# Generated deterministically by seda-macro-lef-normalizer-v1; recipe orfs-asap7-fakeram-m4-v1.
VERSION 5.8 ;
BUSBITCHARS "[]" ;
DIVIDERCHAR "/" ;

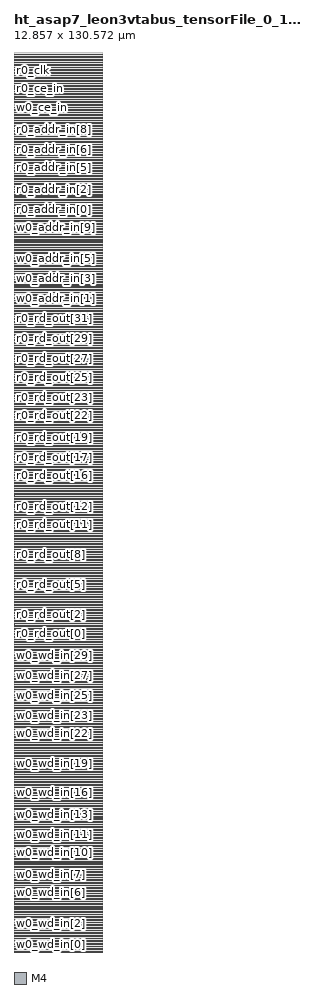
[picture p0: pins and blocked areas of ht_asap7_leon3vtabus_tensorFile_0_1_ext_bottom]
MACRO ht_asap7_leon3vtabus_tensorFile_0_1_ext_bottom
  FOREIGN ht_asap7_leon3vtabus_tensorFile_0_1_ext_bottom 0 0 ;
  CLASS BLOCK ;
  ORIGIN 0 0 ;
  SIZE 12.857 BY 130.572 ;
  SYMMETRY X Y R90 ;
  PIN w0_wd_in[0]
    DIRECTION INPUT ;
    USE SIGNAL ;
    SHAPE ABUTMENT ;
    PORT
      LAYER M4 ;
      RECT 0 0.048 0.024 0.072 ;
    END
  END w0_wd_in[0]
  PIN w0_wd_in[1]
    DIRECTION INPUT ;
    USE SIGNAL ;
    SHAPE ABUTMENT ;
    PORT
      LAYER M4 ;
      RECT 0 1.488 0.024 1.512 ;
    END
  END w0_wd_in[1]
  PIN w0_wd_in[2]
    DIRECTION INPUT ;
    USE SIGNAL ;
    SHAPE ABUTMENT ;
    PORT
      LAYER M4 ;
      RECT 0 2.928 0.024 2.952 ;
    END
  END w0_wd_in[2]
  PIN w0_wd_in[3]
    DIRECTION INPUT ;
    USE SIGNAL ;
    SHAPE ABUTMENT ;
    PORT
      LAYER M4 ;
      RECT 0 4.368 0.024 4.392 ;
    END
  END w0_wd_in[3]
  PIN w0_wd_in[4]
    DIRECTION INPUT ;
    USE SIGNAL ;
    SHAPE ABUTMENT ;
    PORT
      LAYER M4 ;
      RECT 0 5.808 0.024 5.832 ;
    END
  END w0_wd_in[4]
  PIN w0_wd_in[5]
    DIRECTION INPUT ;
    USE SIGNAL ;
    SHAPE ABUTMENT ;
    PORT
      LAYER M4 ;
      RECT 0 7.248 0.024 7.272 ;
    END
  END w0_wd_in[5]
  PIN w0_wd_in[6]
    DIRECTION INPUT ;
    USE SIGNAL ;
    SHAPE ABUTMENT ;
    PORT
      LAYER M4 ;
      RECT 0 8.688 0.024 8.712 ;
    END
  END w0_wd_in[6]
  PIN w0_wd_in[7]
    DIRECTION INPUT ;
    USE SIGNAL ;
    SHAPE ABUTMENT ;
    PORT
      LAYER M4 ;
      RECT 0 10.128 0.024 10.152 ;
    END
  END w0_wd_in[7]
  PIN w0_wd_in[8]
    DIRECTION INPUT ;
    USE SIGNAL ;
    SHAPE ABUTMENT ;
    PORT
      LAYER M4 ;
      RECT 0 11.568 0.024 11.592 ;
    END
  END w0_wd_in[8]
  PIN w0_wd_in[9]
    DIRECTION INPUT ;
    USE SIGNAL ;
    SHAPE ABUTMENT ;
    PORT
      LAYER M4 ;
      RECT 0 13.008 0.024 13.032 ;
    END
  END w0_wd_in[9]
  PIN w0_wd_in[10]
    DIRECTION INPUT ;
    USE SIGNAL ;
    SHAPE ABUTMENT ;
    PORT
      LAYER M4 ;
      RECT 0 14.448 0.024 14.472 ;
    END
  END w0_wd_in[10]
  PIN w0_wd_in[11]
    DIRECTION INPUT ;
    USE SIGNAL ;
    SHAPE ABUTMENT ;
    PORT
      LAYER M4 ;
      RECT 0 15.888 0.024 15.912 ;
    END
  END w0_wd_in[11]
  PIN w0_wd_in[12]
    DIRECTION INPUT ;
    USE SIGNAL ;
    SHAPE ABUTMENT ;
    PORT
      LAYER M4 ;
      RECT 0 17.328 0.024 17.352 ;
    END
  END w0_wd_in[12]
  PIN w0_wd_in[13]
    DIRECTION INPUT ;
    USE SIGNAL ;
    SHAPE ABUTMENT ;
    PORT
      LAYER M4 ;
      RECT 0 18.768 0.024 18.792 ;
    END
  END w0_wd_in[13]
  PIN w0_wd_in[14]
    DIRECTION INPUT ;
    USE SIGNAL ;
    SHAPE ABUTMENT ;
    PORT
      LAYER M4 ;
      RECT 0 20.208 0.024 20.232 ;
    END
  END w0_wd_in[14]
  PIN w0_wd_in[15]
    DIRECTION INPUT ;
    USE SIGNAL ;
    SHAPE ABUTMENT ;
    PORT
      LAYER M4 ;
      RECT 0 21.648 0.024 21.672 ;
    END
  END w0_wd_in[15]
  PIN w0_wd_in[16]
    DIRECTION INPUT ;
    USE SIGNAL ;
    SHAPE ABUTMENT ;
    PORT
      LAYER M4 ;
      RECT 0 23.088 0.024 23.112 ;
    END
  END w0_wd_in[16]
  PIN w0_wd_in[17]
    DIRECTION INPUT ;
    USE SIGNAL ;
    SHAPE ABUTMENT ;
    PORT
      LAYER M4 ;
      RECT 0 24.528 0.024 24.552 ;
    END
  END w0_wd_in[17]
  PIN w0_wd_in[18]
    DIRECTION INPUT ;
    USE SIGNAL ;
    SHAPE ABUTMENT ;
    PORT
      LAYER M4 ;
      RECT 0 25.968 0.024 25.992 ;
    END
  END w0_wd_in[18]
  PIN w0_wd_in[19]
    DIRECTION INPUT ;
    USE SIGNAL ;
    SHAPE ABUTMENT ;
    PORT
      LAYER M4 ;
      RECT 0 27.408 0.024 27.432 ;
    END
  END w0_wd_in[19]
  PIN w0_wd_in[20]
    DIRECTION INPUT ;
    USE SIGNAL ;
    SHAPE ABUTMENT ;
    PORT
      LAYER M4 ;
      RECT 0 28.848 0.024 28.872 ;
    END
  END w0_wd_in[20]
  PIN w0_wd_in[21]
    DIRECTION INPUT ;
    USE SIGNAL ;
    SHAPE ABUTMENT ;
    PORT
      LAYER M4 ;
      RECT 0 30.288 0.024 30.312 ;
    END
  END w0_wd_in[21]
  PIN w0_wd_in[22]
    DIRECTION INPUT ;
    USE SIGNAL ;
    SHAPE ABUTMENT ;
    PORT
      LAYER M4 ;
      RECT 0 31.728 0.024 31.752 ;
    END
  END w0_wd_in[22]
  PIN w0_wd_in[23]
    DIRECTION INPUT ;
    USE SIGNAL ;
    SHAPE ABUTMENT ;
    PORT
      LAYER M4 ;
      RECT 0 33.168 0.024 33.192 ;
    END
  END w0_wd_in[23]
  PIN w0_wd_in[24]
    DIRECTION INPUT ;
    USE SIGNAL ;
    SHAPE ABUTMENT ;
    PORT
      LAYER M4 ;
      RECT 0 34.608 0.024 34.632 ;
    END
  END w0_wd_in[24]
  PIN w0_wd_in[25]
    DIRECTION INPUT ;
    USE SIGNAL ;
    SHAPE ABUTMENT ;
    PORT
      LAYER M4 ;
      RECT 0 36.048 0.024 36.072 ;
    END
  END w0_wd_in[25]
  PIN w0_wd_in[26]
    DIRECTION INPUT ;
    USE SIGNAL ;
    SHAPE ABUTMENT ;
    PORT
      LAYER M4 ;
      RECT 0 37.488 0.024 37.512 ;
    END
  END w0_wd_in[26]
  PIN w0_wd_in[27]
    DIRECTION INPUT ;
    USE SIGNAL ;
    SHAPE ABUTMENT ;
    PORT
      LAYER M4 ;
      RECT 0 38.928 0.024 38.952 ;
    END
  END w0_wd_in[27]
  PIN w0_wd_in[28]
    DIRECTION INPUT ;
    USE SIGNAL ;
    SHAPE ABUTMENT ;
    PORT
      LAYER M4 ;
      RECT 0 40.368 0.024 40.392 ;
    END
  END w0_wd_in[28]
  PIN w0_wd_in[29]
    DIRECTION INPUT ;
    USE SIGNAL ;
    SHAPE ABUTMENT ;
    PORT
      LAYER M4 ;
      RECT 0 41.808 0.024 41.832 ;
    END
  END w0_wd_in[29]
  PIN w0_wd_in[30]
    DIRECTION INPUT ;
    USE SIGNAL ;
    SHAPE ABUTMENT ;
    PORT
      LAYER M4 ;
      RECT 0 43.248 0.024 43.272 ;
    END
  END w0_wd_in[30]
  PIN w0_wd_in[31]
    DIRECTION INPUT ;
    USE SIGNAL ;
    SHAPE ABUTMENT ;
    PORT
      LAYER M4 ;
      RECT 0 44.688 0.024 44.712 ;
    END
  END w0_wd_in[31]
  PIN r0_rd_out[0]
    DIRECTION OUTPUT ;
    USE SIGNAL ;
    SHAPE ABUTMENT ;
    PORT
      LAYER M4 ;
      RECT 0 46.128 0.024 46.152 ;
    END
  END r0_rd_out[0]
  PIN r0_rd_out[1]
    DIRECTION OUTPUT ;
    USE SIGNAL ;
    SHAPE ABUTMENT ;
    PORT
      LAYER M4 ;
      RECT 0 47.568 0.024 47.592 ;
    END
  END r0_rd_out[1]
  PIN r0_rd_out[2]
    DIRECTION OUTPUT ;
    USE SIGNAL ;
    SHAPE ABUTMENT ;
    PORT
      LAYER M4 ;
      RECT 0 49.008 0.024 49.032 ;
    END
  END r0_rd_out[2]
  PIN r0_rd_out[3]
    DIRECTION OUTPUT ;
    USE SIGNAL ;
    SHAPE ABUTMENT ;
    PORT
      LAYER M4 ;
      RECT 0 50.448 0.024 50.472 ;
    END
  END r0_rd_out[3]
  PIN r0_rd_out[4]
    DIRECTION OUTPUT ;
    USE SIGNAL ;
    SHAPE ABUTMENT ;
    PORT
      LAYER M4 ;
      RECT 0 51.888 0.024 51.912 ;
    END
  END r0_rd_out[4]
  PIN r0_rd_out[5]
    DIRECTION OUTPUT ;
    USE SIGNAL ;
    SHAPE ABUTMENT ;
    PORT
      LAYER M4 ;
      RECT 0 53.328 0.024 53.352 ;
    END
  END r0_rd_out[5]
  PIN r0_rd_out[6]
    DIRECTION OUTPUT ;
    USE SIGNAL ;
    SHAPE ABUTMENT ;
    PORT
      LAYER M4 ;
      RECT 0 54.768 0.024 54.792 ;
    END
  END r0_rd_out[6]
  PIN r0_rd_out[7]
    DIRECTION OUTPUT ;
    USE SIGNAL ;
    SHAPE ABUTMENT ;
    PORT
      LAYER M4 ;
      RECT 0 56.208 0.024 56.232 ;
    END
  END r0_rd_out[7]
  PIN r0_rd_out[8]
    DIRECTION OUTPUT ;
    USE SIGNAL ;
    SHAPE ABUTMENT ;
    PORT
      LAYER M4 ;
      RECT 0 57.648 0.024 57.672 ;
    END
  END r0_rd_out[8]
  PIN r0_rd_out[9]
    DIRECTION OUTPUT ;
    USE SIGNAL ;
    SHAPE ABUTMENT ;
    PORT
      LAYER M4 ;
      RECT 0 59.088 0.024 59.112 ;
    END
  END r0_rd_out[9]
  PIN r0_rd_out[10]
    DIRECTION OUTPUT ;
    USE SIGNAL ;
    SHAPE ABUTMENT ;
    PORT
      LAYER M4 ;
      RECT 0 60.528 0.024 60.552 ;
    END
  END r0_rd_out[10]
  PIN r0_rd_out[11]
    DIRECTION OUTPUT ;
    USE SIGNAL ;
    SHAPE ABUTMENT ;
    PORT
      LAYER M4 ;
      RECT 0 61.968 0.024 61.992 ;
    END
  END r0_rd_out[11]
  PIN r0_rd_out[12]
    DIRECTION OUTPUT ;
    USE SIGNAL ;
    SHAPE ABUTMENT ;
    PORT
      LAYER M4 ;
      RECT 0 63.408 0.024 63.432 ;
    END
  END r0_rd_out[12]
  PIN r0_rd_out[13]
    DIRECTION OUTPUT ;
    USE SIGNAL ;
    SHAPE ABUTMENT ;
    PORT
      LAYER M4 ;
      RECT 0 64.848 0.024 64.872 ;
    END
  END r0_rd_out[13]
  PIN r0_rd_out[14]
    DIRECTION OUTPUT ;
    USE SIGNAL ;
    SHAPE ABUTMENT ;
    PORT
      LAYER M4 ;
      RECT 0 66.288 0.024 66.312 ;
    END
  END r0_rd_out[14]
  PIN r0_rd_out[15]
    DIRECTION OUTPUT ;
    USE SIGNAL ;
    SHAPE ABUTMENT ;
    PORT
      LAYER M4 ;
      RECT 0 67.728 0.024 67.752 ;
    END
  END r0_rd_out[15]
  PIN r0_rd_out[16]
    DIRECTION OUTPUT ;
    USE SIGNAL ;
    SHAPE ABUTMENT ;
    PORT
      LAYER M4 ;
      RECT 0 69.168 0.024 69.192 ;
    END
  END r0_rd_out[16]
  PIN r0_rd_out[17]
    DIRECTION OUTPUT ;
    USE SIGNAL ;
    SHAPE ABUTMENT ;
    PORT
      LAYER M4 ;
      RECT 0 70.608 0.024 70.632 ;
    END
  END r0_rd_out[17]
  PIN r0_rd_out[18]
    DIRECTION OUTPUT ;
    USE SIGNAL ;
    SHAPE ABUTMENT ;
    PORT
      LAYER M4 ;
      RECT 0 72.048 0.024 72.072 ;
    END
  END r0_rd_out[18]
  PIN r0_rd_out[19]
    DIRECTION OUTPUT ;
    USE SIGNAL ;
    SHAPE ABUTMENT ;
    PORT
      LAYER M4 ;
      RECT 0 73.488 0.024 73.512 ;
    END
  END r0_rd_out[19]
  PIN r0_rd_out[20]
    DIRECTION OUTPUT ;
    USE SIGNAL ;
    SHAPE ABUTMENT ;
    PORT
      LAYER M4 ;
      RECT 0 74.928 0.024 74.952 ;
    END
  END r0_rd_out[20]
  PIN r0_rd_out[21]
    DIRECTION OUTPUT ;
    USE SIGNAL ;
    SHAPE ABUTMENT ;
    PORT
      LAYER M4 ;
      RECT 0 76.368 0.024 76.392 ;
    END
  END r0_rd_out[21]
  PIN r0_rd_out[22]
    DIRECTION OUTPUT ;
    USE SIGNAL ;
    SHAPE ABUTMENT ;
    PORT
      LAYER M4 ;
      RECT 0 77.808 0.024 77.832 ;
    END
  END r0_rd_out[22]
  PIN r0_rd_out[23]
    DIRECTION OUTPUT ;
    USE SIGNAL ;
    SHAPE ABUTMENT ;
    PORT
      LAYER M4 ;
      RECT 0 79.248 0.024 79.272 ;
    END
  END r0_rd_out[23]
  PIN r0_rd_out[24]
    DIRECTION OUTPUT ;
    USE SIGNAL ;
    SHAPE ABUTMENT ;
    PORT
      LAYER M4 ;
      RECT 0 80.688 0.024 80.712 ;
    END
  END r0_rd_out[24]
  PIN r0_rd_out[25]
    DIRECTION OUTPUT ;
    USE SIGNAL ;
    SHAPE ABUTMENT ;
    PORT
      LAYER M4 ;
      RECT 0 82.128 0.024 82.152 ;
    END
  END r0_rd_out[25]
  PIN r0_rd_out[26]
    DIRECTION OUTPUT ;
    USE SIGNAL ;
    SHAPE ABUTMENT ;
    PORT
      LAYER M4 ;
      RECT 0 83.568 0.024 83.592 ;
    END
  END r0_rd_out[26]
  PIN r0_rd_out[27]
    DIRECTION OUTPUT ;
    USE SIGNAL ;
    SHAPE ABUTMENT ;
    PORT
      LAYER M4 ;
      RECT 0 85.008 0.024 85.032 ;
    END
  END r0_rd_out[27]
  PIN r0_rd_out[28]
    DIRECTION OUTPUT ;
    USE SIGNAL ;
    SHAPE ABUTMENT ;
    PORT
      LAYER M4 ;
      RECT 0 86.448 0.024 86.472 ;
    END
  END r0_rd_out[28]
  PIN r0_rd_out[29]
    DIRECTION OUTPUT ;
    USE SIGNAL ;
    SHAPE ABUTMENT ;
    PORT
      LAYER M4 ;
      RECT 0 87.888 0.024 87.912 ;
    END
  END r0_rd_out[29]
  PIN r0_rd_out[30]
    DIRECTION OUTPUT ;
    USE SIGNAL ;
    SHAPE ABUTMENT ;
    PORT
      LAYER M4 ;
      RECT 0 89.328 0.024 89.352 ;
    END
  END r0_rd_out[30]
  PIN r0_rd_out[31]
    DIRECTION OUTPUT ;
    USE SIGNAL ;
    SHAPE ABUTMENT ;
    PORT
      LAYER M4 ;
      RECT 0 90.768 0.024 90.792 ;
    END
  END r0_rd_out[31]
  PIN w0_addr_in[0]
    DIRECTION INPUT ;
    USE SIGNAL ;
    SHAPE ABUTMENT ;
    PORT
      LAYER M4 ;
      RECT 0 92.208 0.024 92.232 ;
    END
  END w0_addr_in[0]
  PIN w0_addr_in[1]
    DIRECTION INPUT ;
    USE SIGNAL ;
    SHAPE ABUTMENT ;
    PORT
      LAYER M4 ;
      RECT 0 93.648 0.024 93.672 ;
    END
  END w0_addr_in[1]
  PIN w0_addr_in[2]
    DIRECTION INPUT ;
    USE SIGNAL ;
    SHAPE ABUTMENT ;
    PORT
      LAYER M4 ;
      RECT 0 95.088 0.024 95.112 ;
    END
  END w0_addr_in[2]
  PIN w0_addr_in[3]
    DIRECTION INPUT ;
    USE SIGNAL ;
    SHAPE ABUTMENT ;
    PORT
      LAYER M4 ;
      RECT 0 96.528 0.024 96.552 ;
    END
  END w0_addr_in[3]
  PIN w0_addr_in[4]
    DIRECTION INPUT ;
    USE SIGNAL ;
    SHAPE ABUTMENT ;
    PORT
      LAYER M4 ;
      RECT 0 97.968 0.024 97.992 ;
    END
  END w0_addr_in[4]
  PIN w0_addr_in[5]
    DIRECTION INPUT ;
    USE SIGNAL ;
    SHAPE ABUTMENT ;
    PORT
      LAYER M4 ;
      RECT 0 99.408 0.024 99.432 ;
    END
  END w0_addr_in[5]
  PIN w0_addr_in[6]
    DIRECTION INPUT ;
    USE SIGNAL ;
    SHAPE ABUTMENT ;
    PORT
      LAYER M4 ;
      RECT 0 100.848 0.024 100.872 ;
    END
  END w0_addr_in[6]
  PIN w0_addr_in[7]
    DIRECTION INPUT ;
    USE SIGNAL ;
    SHAPE ABUTMENT ;
    PORT
      LAYER M4 ;
      RECT 0 102.288 0.024 102.312 ;
    END
  END w0_addr_in[7]
  PIN w0_addr_in[8]
    DIRECTION INPUT ;
    USE SIGNAL ;
    SHAPE ABUTMENT ;
    PORT
      LAYER M4 ;
      RECT 0 103.728 0.024 103.752 ;
    END
  END w0_addr_in[8]
  PIN w0_addr_in[9]
    DIRECTION INPUT ;
    USE SIGNAL ;
    SHAPE ABUTMENT ;
    PORT
      LAYER M4 ;
      RECT 0 105.168 0.024 105.192 ;
    END
  END w0_addr_in[9]
  PIN r0_addr_in[0]
    DIRECTION INPUT ;
    USE SIGNAL ;
    SHAPE ABUTMENT ;
    PORT
      LAYER M4 ;
      RECT 0 106.608 0.024 106.632 ;
    END
  END r0_addr_in[0]
  PIN r0_addr_in[1]
    DIRECTION INPUT ;
    USE SIGNAL ;
    SHAPE ABUTMENT ;
    PORT
      LAYER M4 ;
      RECT 0 108.048 0.024 108.072 ;
    END
  END r0_addr_in[1]
  PIN r0_addr_in[2]
    DIRECTION INPUT ;
    USE SIGNAL ;
    SHAPE ABUTMENT ;
    PORT
      LAYER M4 ;
      RECT 0 109.488 0.024 109.512 ;
    END
  END r0_addr_in[2]
  PIN r0_addr_in[3]
    DIRECTION INPUT ;
    USE SIGNAL ;
    SHAPE ABUTMENT ;
    PORT
      LAYER M4 ;
      RECT 0 110.928 0.024 110.952 ;
    END
  END r0_addr_in[3]
  PIN r0_addr_in[4]
    DIRECTION INPUT ;
    USE SIGNAL ;
    SHAPE ABUTMENT ;
    PORT
      LAYER M4 ;
      RECT 0 112.368 0.024 112.392 ;
    END
  END r0_addr_in[4]
  PIN r0_addr_in[5]
    DIRECTION INPUT ;
    USE SIGNAL ;
    SHAPE ABUTMENT ;
    PORT
      LAYER M4 ;
      RECT 0 113.808 0.024 113.832 ;
    END
  END r0_addr_in[5]
  PIN r0_addr_in[6]
    DIRECTION INPUT ;
    USE SIGNAL ;
    SHAPE ABUTMENT ;
    PORT
      LAYER M4 ;
      RECT 0 115.248 0.024 115.272 ;
    END
  END r0_addr_in[6]
  PIN r0_addr_in[7]
    DIRECTION INPUT ;
    USE SIGNAL ;
    SHAPE ABUTMENT ;
    PORT
      LAYER M4 ;
      RECT 0 116.688 0.024 116.712 ;
    END
  END r0_addr_in[7]
  PIN r0_addr_in[8]
    DIRECTION INPUT ;
    USE SIGNAL ;
    SHAPE ABUTMENT ;
    PORT
      LAYER M4 ;
      RECT 0 118.128 0.024 118.152 ;
    END
  END r0_addr_in[8]
  PIN r0_addr_in[9]
    DIRECTION INPUT ;
    USE SIGNAL ;
    SHAPE ABUTMENT ;
    PORT
      LAYER M4 ;
      RECT 0 119.568 0.024 119.592 ;
    END
  END r0_addr_in[9]
  PIN w0_we_in
    DIRECTION INPUT ;
    USE SIGNAL ;
    SHAPE ABUTMENT ;
    PORT
      LAYER M4 ;
      RECT 0 121.008 0.024 121.032 ;
    END
  END w0_we_in
  PIN w0_ce_in
    DIRECTION INPUT ;
    USE SIGNAL ;
    SHAPE ABUTMENT ;
    PORT
      LAYER M4 ;
      RECT 0 122.448 0.024 122.472 ;
    END
  END w0_ce_in
  PIN w0_clk
    DIRECTION INPUT ;
    USE SIGNAL ;
    SHAPE ABUTMENT ;
    PORT
      LAYER M4 ;
      RECT 0 123.888 0.024 123.912 ;
    END
  END w0_clk
  PIN r0_ce_in
    DIRECTION INPUT ;
    USE SIGNAL ;
    SHAPE ABUTMENT ;
    PORT
      LAYER M4 ;
      RECT 0 125.328 0.024 125.352 ;
    END
  END r0_ce_in
  PIN r0_clk
    DIRECTION INPUT ;
    USE SIGNAL ;
    SHAPE ABUTMENT ;
    PORT
      LAYER M4 ;
      RECT 0 126.768 0.024 126.792 ;
    END
  END r0_clk
  PIN VSS
    DIRECTION INOUT ;
    USE GROUND ;
    PORT
      LAYER M4 ;
      RECT 0.048 0 12.809 0.096 ;
      RECT 0.048 0.768 12.809 0.864 ;
      RECT 0.048 1.536 12.809 1.632 ;
      RECT 0.048 2.304 12.809 2.4 ;
      RECT 0.048 3.072 12.809 3.168 ;
      RECT 0.048 3.84 12.809 3.936 ;
      RECT 0.048 4.608 12.809 4.704 ;
      RECT 0.048 5.376 12.809 5.472 ;
      RECT 0.048 6.144 12.809 6.24 ;
      RECT 0.048 6.912 12.809 7.008 ;
      RECT 0.048 7.68 12.809 7.776 ;
      RECT 0.048 8.448 12.809 8.544 ;
      RECT 0.048 9.216 12.809 9.312 ;
      RECT 0.048 9.984 12.809 10.08 ;
      RECT 0.048 10.752 12.809 10.848 ;
      RECT 0.048 11.52 12.809 11.616 ;
      RECT 0.048 12.288 12.809 12.384 ;
      RECT 0.048 13.056 12.809 13.152 ;
      RECT 0.048 13.824 12.809 13.92 ;
      RECT 0.048 14.592 12.809 14.688 ;
      RECT 0.048 15.36 12.809 15.456 ;
      RECT 0.048 16.128 12.809 16.224 ;
      RECT 0.048 16.896 12.809 16.992 ;
      RECT 0.048 17.664 12.809 17.76 ;
      RECT 0.048 18.432 12.809 18.528 ;
      RECT 0.048 19.2 12.809 19.296 ;
      RECT 0.048 19.968 12.809 20.064 ;
      RECT 0.048 20.736 12.809 20.832 ;
      RECT 0.048 21.504 12.809 21.6 ;
      RECT 0.048 22.272 12.809 22.368 ;
      RECT 0.048 23.04 12.809 23.136 ;
      RECT 0.048 23.808 12.809 23.904 ;
      RECT 0.048 24.576 12.809 24.672 ;
      RECT 0.048 25.344 12.809 25.44 ;
      RECT 0.048 26.112 12.809 26.208 ;
      RECT 0.048 26.88 12.809 26.976 ;
      RECT 0.048 27.648 12.809 27.744 ;
      RECT 0.048 28.416 12.809 28.512 ;
      RECT 0.048 29.184 12.809 29.28 ;
      RECT 0.048 29.952 12.809 30.048 ;
      RECT 0.048 30.72 12.809 30.816 ;
      RECT 0.048 31.488 12.809 31.584 ;
      RECT 0.048 32.256 12.809 32.352 ;
      RECT 0.048 33.024 12.809 33.12 ;
      RECT 0.048 33.792 12.809 33.888 ;
      RECT 0.048 34.56 12.809 34.656 ;
      RECT 0.048 35.328 12.809 35.424 ;
      RECT 0.048 36.096 12.809 36.192 ;
      RECT 0.048 36.864 12.809 36.96 ;
      RECT 0.048 37.632 12.809 37.728 ;
      RECT 0.048 38.4 12.809 38.496 ;
      RECT 0.048 39.168 12.809 39.264 ;
      RECT 0.048 39.936 12.809 40.032 ;
      RECT 0.048 40.704 12.809 40.8 ;
      RECT 0.048 41.472 12.809 41.568 ;
      RECT 0.048 42.24 12.809 42.336 ;
      RECT 0.048 43.008 12.809 43.104 ;
      RECT 0.048 43.776 12.809 43.872 ;
      RECT 0.048 44.544 12.809 44.64 ;
      RECT 0.048 45.312 12.809 45.408 ;
      RECT 0.048 46.08 12.809 46.176 ;
      RECT 0.048 46.848 12.809 46.944 ;
      RECT 0.048 47.616 12.809 47.712 ;
      RECT 0.048 48.384 12.809 48.48 ;
      RECT 0.048 49.152 12.809 49.248 ;
      RECT 0.048 49.92 12.809 50.016 ;
      RECT 0.048 50.688 12.809 50.784 ;
      RECT 0.048 51.456 12.809 51.552 ;
      RECT 0.048 52.224 12.809 52.32 ;
      RECT 0.048 52.992 12.809 53.088 ;
      RECT 0.048 53.76 12.809 53.856 ;
      RECT 0.048 54.528 12.809 54.624 ;
      RECT 0.048 55.296 12.809 55.392 ;
      RECT 0.048 56.064 12.809 56.16 ;
      RECT 0.048 56.832 12.809 56.928 ;
      RECT 0.048 57.6 12.809 57.696 ;
      RECT 0.048 58.368 12.809 58.464 ;
      RECT 0.048 59.136 12.809 59.232 ;
      RECT 0.048 59.904 12.809 60 ;
      RECT 0.048 60.672 12.809 60.768 ;
      RECT 0.048 61.44 12.809 61.536 ;
      RECT 0.048 62.208 12.809 62.304 ;
      RECT 0.048 62.976 12.809 63.072 ;
      RECT 0.048 63.744 12.809 63.84 ;
      RECT 0.048 64.512 12.809 64.608 ;
      RECT 0.048 65.28 12.809 65.376 ;
      RECT 0.048 66.048 12.809 66.144 ;
      RECT 0.048 66.816 12.809 66.912 ;
      RECT 0.048 67.584 12.809 67.68 ;
      RECT 0.048 68.352 12.809 68.448 ;
      RECT 0.048 69.12 12.809 69.216 ;
      RECT 0.048 69.888 12.809 69.984 ;
      RECT 0.048 70.656 12.809 70.752 ;
      RECT 0.048 71.424 12.809 71.52 ;
      RECT 0.048 72.192 12.809 72.288 ;
      RECT 0.048 72.96 12.809 73.056 ;
      RECT 0.048 73.728 12.809 73.824 ;
      RECT 0.048 74.496 12.809 74.592 ;
      RECT 0.048 75.264 12.809 75.36 ;
      RECT 0.048 76.032 12.809 76.128 ;
      RECT 0.048 76.8 12.809 76.896 ;
      RECT 0.048 77.568 12.809 77.664 ;
      RECT 0.048 78.336 12.809 78.432 ;
      RECT 0.048 79.104 12.809 79.2 ;
      RECT 0.048 79.872 12.809 79.968 ;
      RECT 0.048 80.64 12.809 80.736 ;
      RECT 0.048 81.408 12.809 81.504 ;
      RECT 0.048 82.176 12.809 82.272 ;
      RECT 0.048 82.944 12.809 83.04 ;
      RECT 0.048 83.712 12.809 83.808 ;
      RECT 0.048 84.48 12.809 84.576 ;
      RECT 0.048 85.248 12.809 85.344 ;
      RECT 0.048 86.016 12.809 86.112 ;
      RECT 0.048 86.784 12.809 86.88 ;
      RECT 0.048 87.552 12.809 87.648 ;
      RECT 0.048 88.32 12.809 88.416 ;
      RECT 0.048 89.088 12.809 89.184 ;
      RECT 0.048 89.856 12.809 89.952 ;
      RECT 0.048 90.624 12.809 90.72 ;
      RECT 0.048 91.392 12.809 91.488 ;
      RECT 0.048 92.16 12.809 92.256 ;
      RECT 0.048 92.928 12.809 93.024 ;
      RECT 0.048 93.696 12.809 93.792 ;
      RECT 0.048 94.464 12.809 94.56 ;
      RECT 0.048 95.232 12.809 95.328 ;
      RECT 0.048 96 12.809 96.096 ;
      RECT 0.048 96.768 12.809 96.864 ;
      RECT 0.048 97.536 12.809 97.632 ;
      RECT 0.048 98.304 12.809 98.4 ;
      RECT 0.048 99.072 12.809 99.168 ;
      RECT 0.048 99.84 12.809 99.936 ;
      RECT 0.048 100.608 12.809 100.704 ;
      RECT 0.048 101.376 12.809 101.472 ;
      RECT 0.048 102.144 12.809 102.24 ;
      RECT 0.048 102.912 12.809 103.008 ;
      RECT 0.048 103.68 12.809 103.776 ;
      RECT 0.048 104.448 12.809 104.544 ;
      RECT 0.048 105.216 12.809 105.312 ;
      RECT 0.048 105.984 12.809 106.08 ;
      RECT 0.048 106.752 12.809 106.848 ;
      RECT 0.048 107.52 12.809 107.616 ;
      RECT 0.048 108.288 12.809 108.384 ;
      RECT 0.048 109.056 12.809 109.152 ;
      RECT 0.048 109.824 12.809 109.92 ;
      RECT 0.048 110.592 12.809 110.688 ;
      RECT 0.048 111.36 12.809 111.456 ;
      RECT 0.048 112.128 12.809 112.224 ;
      RECT 0.048 112.896 12.809 112.992 ;
      RECT 0.048 113.664 12.809 113.76 ;
      RECT 0.048 114.432 12.809 114.528 ;
      RECT 0.048 115.2 12.809 115.296 ;
      RECT 0.048 115.968 12.809 116.064 ;
      RECT 0.048 116.736 12.809 116.832 ;
      RECT 0.048 117.504 12.809 117.6 ;
      RECT 0.048 118.272 12.809 118.368 ;
      RECT 0.048 119.04 12.809 119.136 ;
      RECT 0.048 119.808 12.809 119.904 ;
      RECT 0.048 120.576 12.809 120.672 ;
      RECT 0.048 121.344 12.809 121.44 ;
      RECT 0.048 122.112 12.809 122.208 ;
      RECT 0.048 122.88 12.809 122.976 ;
      RECT 0.048 123.648 12.809 123.744 ;
      RECT 0.048 124.416 12.809 124.512 ;
      RECT 0.048 125.184 12.809 125.28 ;
      RECT 0.048 125.952 12.809 126.048 ;
      RECT 0.048 126.72 12.809 126.816 ;
      RECT 0.048 127.488 12.809 127.584 ;
      RECT 0.048 128.256 12.809 128.352 ;
      RECT 0.048 129.024 12.809 129.12 ;
      RECT 0.048 129.792 12.809 129.888 ;
    END
  END VSS
  PIN VDD
    DIRECTION INOUT ;
    USE POWER ;
    PORT
      LAYER M4 ;
      RECT 0.048 0.384 12.809 0.48 ;
      RECT 0.048 1.152 12.809 1.248 ;
      RECT 0.048 1.92 12.809 2.016 ;
      RECT 0.048 2.688 12.809 2.784 ;
      RECT 0.048 3.456 12.809 3.552 ;
      RECT 0.048 4.224 12.809 4.32 ;
      RECT 0.048 4.992 12.809 5.088 ;
      RECT 0.048 5.76 12.809 5.856 ;
      RECT 0.048 6.528 12.809 6.624 ;
      RECT 0.048 7.296 12.809 7.392 ;
      RECT 0.048 8.064 12.809 8.16 ;
      RECT 0.048 8.832 12.809 8.928 ;
      RECT 0.048 9.6 12.809 9.696 ;
      RECT 0.048 10.368 12.809 10.464 ;
      RECT 0.048 11.136 12.809 11.232 ;
      RECT 0.048 11.904 12.809 12 ;
      RECT 0.048 12.672 12.809 12.768 ;
      RECT 0.048 13.44 12.809 13.536 ;
      RECT 0.048 14.208 12.809 14.304 ;
      RECT 0.048 14.976 12.809 15.072 ;
      RECT 0.048 15.744 12.809 15.84 ;
      RECT 0.048 16.512 12.809 16.608 ;
      RECT 0.048 17.28 12.809 17.376 ;
      RECT 0.048 18.048 12.809 18.144 ;
      RECT 0.048 18.816 12.809 18.912 ;
      RECT 0.048 19.584 12.809 19.68 ;
      RECT 0.048 20.352 12.809 20.448 ;
      RECT 0.048 21.12 12.809 21.216 ;
      RECT 0.048 21.888 12.809 21.984 ;
      RECT 0.048 22.656 12.809 22.752 ;
      RECT 0.048 23.424 12.809 23.52 ;
      RECT 0.048 24.192 12.809 24.288 ;
      RECT 0.048 24.96 12.809 25.056 ;
      RECT 0.048 25.728 12.809 25.824 ;
      RECT 0.048 26.496 12.809 26.592 ;
      RECT 0.048 27.264 12.809 27.36 ;
      RECT 0.048 28.032 12.809 28.128 ;
      RECT 0.048 28.8 12.809 28.896 ;
      RECT 0.048 29.568 12.809 29.664 ;
      RECT 0.048 30.336 12.809 30.432 ;
      RECT 0.048 31.104 12.809 31.2 ;
      RECT 0.048 31.872 12.809 31.968 ;
      RECT 0.048 32.64 12.809 32.736 ;
      RECT 0.048 33.408 12.809 33.504 ;
      RECT 0.048 34.176 12.809 34.272 ;
      RECT 0.048 34.944 12.809 35.04 ;
      RECT 0.048 35.712 12.809 35.808 ;
      RECT 0.048 36.48 12.809 36.576 ;
      RECT 0.048 37.248 12.809 37.344 ;
      RECT 0.048 38.016 12.809 38.112 ;
      RECT 0.048 38.784 12.809 38.88 ;
      RECT 0.048 39.552 12.809 39.648 ;
      RECT 0.048 40.32 12.809 40.416 ;
      RECT 0.048 41.088 12.809 41.184 ;
      RECT 0.048 41.856 12.809 41.952 ;
      RECT 0.048 42.624 12.809 42.72 ;
      RECT 0.048 43.392 12.809 43.488 ;
      RECT 0.048 44.16 12.809 44.256 ;
      RECT 0.048 44.928 12.809 45.024 ;
      RECT 0.048 45.696 12.809 45.792 ;
      RECT 0.048 46.464 12.809 46.56 ;
      RECT 0.048 47.232 12.809 47.328 ;
      RECT 0.048 48 12.809 48.096 ;
      RECT 0.048 48.768 12.809 48.864 ;
      RECT 0.048 49.536 12.809 49.632 ;
      RECT 0.048 50.304 12.809 50.4 ;
      RECT 0.048 51.072 12.809 51.168 ;
      RECT 0.048 51.84 12.809 51.936 ;
      RECT 0.048 52.608 12.809 52.704 ;
      RECT 0.048 53.376 12.809 53.472 ;
      RECT 0.048 54.144 12.809 54.24 ;
      RECT 0.048 54.912 12.809 55.008 ;
      RECT 0.048 55.68 12.809 55.776 ;
      RECT 0.048 56.448 12.809 56.544 ;
      RECT 0.048 57.216 12.809 57.312 ;
      RECT 0.048 57.984 12.809 58.08 ;
      RECT 0.048 58.752 12.809 58.848 ;
      RECT 0.048 59.52 12.809 59.616 ;
      RECT 0.048 60.288 12.809 60.384 ;
      RECT 0.048 61.056 12.809 61.152 ;
      RECT 0.048 61.824 12.809 61.92 ;
      RECT 0.048 62.592 12.809 62.688 ;
      RECT 0.048 63.36 12.809 63.456 ;
      RECT 0.048 64.128 12.809 64.224 ;
      RECT 0.048 64.896 12.809 64.992 ;
      RECT 0.048 65.664 12.809 65.76 ;
      RECT 0.048 66.432 12.809 66.528 ;
      RECT 0.048 67.2 12.809 67.296 ;
      RECT 0.048 67.968 12.809 68.064 ;
      RECT 0.048 68.736 12.809 68.832 ;
      RECT 0.048 69.504 12.809 69.6 ;
      RECT 0.048 70.272 12.809 70.368 ;
      RECT 0.048 71.04 12.809 71.136 ;
      RECT 0.048 71.808 12.809 71.904 ;
      RECT 0.048 72.576 12.809 72.672 ;
      RECT 0.048 73.344 12.809 73.44 ;
      RECT 0.048 74.112 12.809 74.208 ;
      RECT 0.048 74.88 12.809 74.976 ;
      RECT 0.048 75.648 12.809 75.744 ;
      RECT 0.048 76.416 12.809 76.512 ;
      RECT 0.048 77.184 12.809 77.28 ;
      RECT 0.048 77.952 12.809 78.048 ;
      RECT 0.048 78.72 12.809 78.816 ;
      RECT 0.048 79.488 12.809 79.584 ;
      RECT 0.048 80.256 12.809 80.352 ;
      RECT 0.048 81.024 12.809 81.12 ;
      RECT 0.048 81.792 12.809 81.888 ;
      RECT 0.048 82.56 12.809 82.656 ;
      RECT 0.048 83.328 12.809 83.424 ;
      RECT 0.048 84.096 12.809 84.192 ;
      RECT 0.048 84.864 12.809 84.96 ;
      RECT 0.048 85.632 12.809 85.728 ;
      RECT 0.048 86.4 12.809 86.496 ;
      RECT 0.048 87.168 12.809 87.264 ;
      RECT 0.048 87.936 12.809 88.032 ;
      RECT 0.048 88.704 12.809 88.8 ;
      RECT 0.048 89.472 12.809 89.568 ;
      RECT 0.048 90.24 12.809 90.336 ;
      RECT 0.048 91.008 12.809 91.104 ;
      RECT 0.048 91.776 12.809 91.872 ;
      RECT 0.048 92.544 12.809 92.64 ;
      RECT 0.048 93.312 12.809 93.408 ;
      RECT 0.048 94.08 12.809 94.176 ;
      RECT 0.048 94.848 12.809 94.944 ;
      RECT 0.048 95.616 12.809 95.712 ;
      RECT 0.048 96.384 12.809 96.48 ;
      RECT 0.048 97.152 12.809 97.248 ;
      RECT 0.048 97.92 12.809 98.016 ;
      RECT 0.048 98.688 12.809 98.784 ;
      RECT 0.048 99.456 12.809 99.552 ;
      RECT 0.048 100.224 12.809 100.32 ;
      RECT 0.048 100.992 12.809 101.088 ;
      RECT 0.048 101.76 12.809 101.856 ;
      RECT 0.048 102.528 12.809 102.624 ;
      RECT 0.048 103.296 12.809 103.392 ;
      RECT 0.048 104.064 12.809 104.16 ;
      RECT 0.048 104.832 12.809 104.928 ;
      RECT 0.048 105.6 12.809 105.696 ;
      RECT 0.048 106.368 12.809 106.464 ;
      RECT 0.048 107.136 12.809 107.232 ;
      RECT 0.048 107.904 12.809 108 ;
      RECT 0.048 108.672 12.809 108.768 ;
      RECT 0.048 109.44 12.809 109.536 ;
      RECT 0.048 110.208 12.809 110.304 ;
      RECT 0.048 110.976 12.809 111.072 ;
      RECT 0.048 111.744 12.809 111.84 ;
      RECT 0.048 112.512 12.809 112.608 ;
      RECT 0.048 113.28 12.809 113.376 ;
      RECT 0.048 114.048 12.809 114.144 ;
      RECT 0.048 114.816 12.809 114.912 ;
      RECT 0.048 115.584 12.809 115.68 ;
      RECT 0.048 116.352 12.809 116.448 ;
      RECT 0.048 117.12 12.809 117.216 ;
      RECT 0.048 117.888 12.809 117.984 ;
      RECT 0.048 118.656 12.809 118.752 ;
      RECT 0.048 119.424 12.809 119.52 ;
      RECT 0.048 120.192 12.809 120.288 ;
      RECT 0.048 120.96 12.809 121.056 ;
      RECT 0.048 121.728 12.809 121.824 ;
      RECT 0.048 122.496 12.809 122.592 ;
      RECT 0.048 123.264 12.809 123.36 ;
      RECT 0.048 124.032 12.809 124.128 ;
      RECT 0.048 124.8 12.809 124.896 ;
      RECT 0.048 125.568 12.809 125.664 ;
      RECT 0.048 126.336 12.809 126.432 ;
      RECT 0.048 127.104 12.809 127.2 ;
      RECT 0.048 127.872 12.809 127.968 ;
      RECT 0.048 128.64 12.809 128.736 ;
      RECT 0.048 129.408 12.809 129.504 ;
      RECT 0.048 130.176 12.809 130.272 ;
    END
  END VDD
  OBS
    LAYER M1 ;
    RECT 0 0 12.857 130.572 ;
    LAYER M2 ;
    RECT 0 0 12.857 130.572 ;
    LAYER M3 ;
    RECT 0 0 12.857 130.572 ;
  END
END ht_asap7_leon3vtabus_tensorFile_0_1_ext_bottom

END LIBRARY
